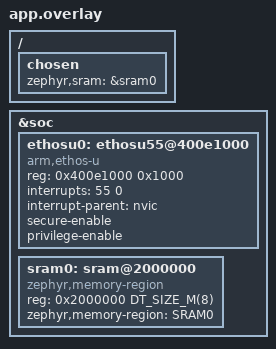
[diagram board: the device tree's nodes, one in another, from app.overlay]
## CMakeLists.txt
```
# SPDX-License-Identifier: Apache-2.0

cmake_minimum_required(VERSION 3.20.0)

# Select the AI layer's Kconfig fragments before Zephyr processes configuration.
list(APPEND EXTRA_CONF_FILE
  "${CMAKE_CURRENT_SOURCE_DIR}/ai_layer/components.conf"
  "${CMAKE_CURRENT_SOURCE_DIR}/ai_layer/operators.conf"
)

# Include the NPU node even when an older build cache has an empty overlay list.
if(NOT DTC_OVERLAY_FILE)
  set(DTC_OVERLAY_FILE "${CMAKE_CURRENT_SOURCE_DIR}/app.overlay")
endif()

find_package(Zephyr REQUIRED HINTS $ENV{ZEPHYR_BASE})
project(my_app)

add_subdirectory(ai_layer)

# Zephyr already provides sys/types.h for AC6; the bare-metal pack shim
# must not shadow it. Only libc++ needs compatibility adjustments here.
if(CMAKE_CXX_COMPILER_ID STREQUAL "ARMClang")
  # AC6 6.24's register coalescer crashes on this pack's quantization code
  # with hard-float at -Og/-O1; -O2 avoids it and keeps the kernel optimized.
  if(CONFIG_FP_HARDABI)
    get_target_property(_et_sources cmsis_executorch SOURCES)
    set(_et_quantize_workaround_applied FALSE)
    foreach(_source IN LISTS _et_sources)
      if(_source MATCHES "[/\\\\]op_quantize\\.cpp$")
        set_property(SOURCE "${_source}" TARGET_DIRECTORY cmsis_executorch
          APPEND PROPERTY COMPILE_OPTIONS -O2)
        set(_et_quantize_workaround_applied TRUE)
      endif()
    endforeach()
    if(NOT _et_quantize_workaround_applied)
      message(FATAL_ERROR
        "AC6 workaround could not find ExecuTorch op_quantize.cpp")
    endif()
  endif()

  # Zephyr's armstdc wrappers use #include_next to chain into AC6's C headers,
  # and AC6 6.24's libc++ wrappers must precede both (notably stddef.h).
  # Explicitly add both system include paths in order: libcxx -> armstdc -> include.
  get_filename_component(_ac6_bin "${CMAKE_CXX_COMPILER}" DIRECTORY)
  get_filename_component(_ac6_include "${_ac6_bin}/../include" ABSOLUTE)
  get_filename_component(_ac6_libcxx "${_ac6_include}/libcxx" ABSOLUTE)
  if(IS_DIRECTORY "${_ac6_libcxx}")
    target_include_directories(zephyr_interface SYSTEM BEFORE INTERFACE
      "$<$<COMPILE_LANGUAGE:CXX>:${_ac6_libcxx}>")
  endif()
  if(IS_DIRECTORY "${_ac6_include}")
    target_include_directories(zephyr_interface SYSTEM INTERFACE
      "${_ac6_include}")
  endif()
  zephyr_compile_options(
    "$<$<COMPILE_LANGUAGE:CXX>:-include${CMAKE_CURRENT_SOURCE_DIR}/src/zephyr_ac6_compat.hpp>")

  # Zephyr's CMake scatter generator disables CONFIG_STATIC_INIT_GNU,
  # omitting the constructor runner and the companion destructor handler.
  if(NOT CONFIG_STATIC_INIT_GNU)
    zephyr_linker_section_configure(SECTION ctors
      INPUT ".init_array*" SORT NAME KEEP
      SYMBOLS __ac6_init_array_start __ac6_init_array_end)
    zephyr_link_libraries("--keep=*.o(.init_array*)")
    target_sources(app PRIVATE src/zephyr_ac6_init.c
      "${ZEPHYR_BASE}/lib/cpp/abi/cpp_dtors.c")
  endif()

  # Zephyr hard-codes microlib for armlink. ExecuTorch's full libc++ needs
  # the standard Arm C runtime (wide strings and AEABI assertions).
  foreach(_elf zephyr_pre0 zephyr_pre1 zephyr_final)
    if(TARGET ${_elf})
      get_target_property(_libs ${_elf} LINK_LIBRARIES)
      list(REMOVE_ITEM _libs "--library_type=microlib")
      set_property(TARGET ${_elf} PROPERTY LINK_LIBRARIES "${_libs}")
    endif()
  endforeach()
endif()

target_sources(app PRIVATE
  src/main.c
  src/arm_embedded_module.cpp
)
target_include_directories(app PRIVATE src)
if(CONFIG_EXECUTORCH_MULTIPLE_TEST)
  target_sources(app PRIVATE src/executorch_multiple_test.cpp)
else()
  target_sources(app PRIVATE src/executorch_test.cpp)
endif()

# The Corstone FVP watches UART output for EOT (0x04). Physical targets must
# not receive this control character, so enable it only from the FVP context.
if(FVP_SHUTDOWN_ON_EOT)
  target_compile_definitions(app PRIVATE FVP_SHUTDOWN_ON_EOT=1)
endif()

# Keep runtime logging consistent with the existing AI layer configuration.
zephyr_compile_definitions(ET_LOG_ENABLED=0)
```

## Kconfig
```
# Copyright 2026 Arm Limited and/or its affiliates.
# SPDX-License-Identifier: Apache-2.0
mainmenu "ExecuTorch example"

choice EXECUTORCH_EXAMPLE
    prompt "ExecuTorch test"
    default EXECUTORCH_SINGLE_TEST

config EXECUTORCH_SINGLE_TEST
    bool "Single TinyCNN forward method"

config EXECUTORCH_MULTIPLE_TEST
    bool "Filter then classify with runtime shape constants"

endchoice

source "Kconfig.zephyr"
```

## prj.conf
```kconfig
# Zephyr driver configuration for the E8 Ethos-U55 with 256 MACs
# per cycle. These are Zephyr Kconfig symbols, not CMSIS-Ethos-U pack settings.
# Alif UART registers require 32-bit MMIO accesses. Byte writes to the
# NS16550 transmit holding register do not start transmission.
CONFIG_UART_NS16550_ACCESS_WORD_ONLY=y

CONFIG_ETHOS_U=y
CONFIG_ETHOS_U55_256=y
CONFIG_ETHOS_U_ARM=y
#CONFIG_ETHOS_U_LOG_LEVEL_NONE=y

# Ethos-U synchronization uses the kernel heap.
CONFIG_HEAP_MEM_POOL_SIZE=16384
# C++ allocations must use a heap initialized by Zephyr, including with AC6.
CONFIG_COMMON_LIBC_MALLOC=y
CONFIG_COMMON_LIBC_MALLOC_ARENA_SIZE=65536
CONFIG_LOG=y
# Keep the boot banner and kernel logs in order with the runtime's direct printf.
CONFIG_LOG_MODE_IMMEDIATE=y
CONFIG_ETHOS_U_LOG_LEVEL_INF=y
CONFIG_CACHE_MANAGEMENT=y
CONFIG_ETHOS_U_DCACHE=y

CONFIG_CPP=y
CONFIG_STD_CPP17=y

# Use the Cortex-M hardware FPU and pass floating-point arguments in FP registers.
CONFIG_FPU=y
CONFIG_FP_HARDABI=y

# Runtime loading uses C++ containers; the runner also prints float logits.
CONFIG_MAIN_STACK_SIZE=16384
CONFIG_REQUIRES_FLOAT_PRINTF=y

# Set y after selecting TinyCNNMultiple.pt2 in the csolution and regenerating ai_layer.
CONFIG_EXECUTORCH_MULTIPLE_TEST=n
```

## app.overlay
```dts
/* Copyright (c) Meta Platforms, Inc. and affiliates.
 * Copyright 2026 Arm Limited and/or its affiliates.
 * SPDX-License-Identifier: Apache-2.0
 */

/* The Ethos-U cannot DMA to the Cortex-M55 DTCM selected by the board DTS.
 * Combine SRAM0 and SRAM1 into one NPU-accessible application RAM region.
 */
/delete-node/ &sram0;
/delete-node/ &sram1;

&soc {
	ethosu0: ethosu55@400e1000 {
		compatible = "arm,ethos-u";
		reg = <0x400e1000 0x1000>;
		interrupts = <55 0>;
		interrupt-parent = <&nvic>;
		secure-enable;
		privilege-enable;
		status = "okay";
	};

	sram0: sram@2000000 {
		compatible = "zephyr,memory-region", "mmio-sram";
		reg = <0x2000000 DT_SIZE_M(8)>;
		zephyr,memory-region = "SRAM0";
	};
};

/ {
	chosen {
		zephyr,sram = &sram0;
	};
};
```

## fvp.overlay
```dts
/* SPDX-License-Identifier: Apache-2.0 */

/* Use ISRAM for writable data because the Ethos-U DMA cannot access DTCM. */
/ {
	chosen {
		zephyr,sram = &isram;
	};
};
```

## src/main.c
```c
/*
 * Copyright (c) 2012-2014 Wind River Systems, Inc.
 *
 * SPDX-License-Identifier: Apache-2.0
 */

#include <errno.h>
#include <inttypes.h>
#include <stdio.h>

#include <zephyr/device.h>
#include <zephyr/devicetree.h>

#include <ethosu_driver.h>

#include "executorch_test.h"

#define NPU_NODE DT_NODELABEL(ethosu0)

static int finish(int result)
{
#ifdef FVP_SHUTDOWN_ON_EOT
	/* fvp_config.txt has shutdown_on_eot=1, so this ends an FVP run promptly. */
	putchar('\x04');
	fflush(stdout);
#endif
	return result;
}

int main(void)
{
	const struct device *npu = DEVICE_DT_GET(NPU_NODE);
	struct ethosu_driver_version version;
	struct ethosu_hw_info hw;
	struct ethosu_driver *drv;
	int ret = 0;

	printf("Hello World! %s\n", CONFIG_BOARD_TARGET);
	printf("Ethos-U55 driver communication check\n");
	printf("Device: %s, base: 0x%08" PRIxPTR ", IRQ: %u\n", npu->name,
	       (uintptr_t)DT_REG_ADDR(NPU_NODE), DT_IRQN(NPU_NODE));

	ethosu_get_driver_version(&version);
	printf("Driver version: %u.%u.%u\n", version.major, version.minor, version.patch);

	/* Do not reserve a driver if initialization failed: reservation would block. */
	if (!device_is_ready(npu)) {
		printf("ERROR: Ethos-U55 device initialization failed. Check the driver logs "
		       "and the board's NPU power, clock and security configuration.\n");
		return finish(-ENODEV);
	}

	drv = ethosu_reserve_driver();
	if (drv == NULL) {
		printf("ERROR: Could not reserve the Ethos-U55 driver.\n");
		return finish(-ENODEV);
	}

	/* This API reads the NPU's ID and CONFIG registers through the core driver. */
	ethosu_get_hw_info(drv, &hw);
	printf("Hardware architecture: %" PRIu32 ".%" PRIu32 ".%" PRIu32 "\n",
	       hw.version.arch_major_rev, hw.version.arch_minor_rev,
	       hw.version.arch_patch_rev);
	printf("Hardware revision: %" PRIu32 ".%" PRIu32 " (status %" PRIu32 ")\n",
	       hw.version.version_major, hw.version.version_minor, hw.version.version_status);
	printf("Product revision: %" PRIu32 "\n", hw.version.product_major);
	printf("Command stream version: %" PRIu32 "\n", hw.cfg.cmd_stream_version);
	printf("Custom DMA: %" PRIu32 "\n", hw.cfg.custom_dma);

	/* macs_per_cc is encoded as log2(MACs per cycle) by the hardware. */
	if (hw.cfg.macs_per_cc < 32U) {
		uint32_t macs = UINT32_C(1) << hw.cfg.macs_per_cc;

		printf("MACs per cycle: %" PRIu32 "\n", macs);
		if (macs != 256U) {
			printf("ERROR: Expected the E8's 256-MAC Ethos-U55 configuration.\n");
			ret = -EINVAL;
		}
	} else {
		printf("ERROR: Invalid MAC configuration: %" PRIu32 "\n", hw.cfg.macs_per_cc);
		ret = -EINVAL;
	}

	ethosu_release_driver(drv);
	if (ret == 0) {
		printf("Ethos-U55 driver communication OK (ID/configuration read; no inference).\n");
		return finish(executorch_run_test());
	}

	return finish(ret);
}
```

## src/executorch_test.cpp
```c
// Copyright 2026 Arm Limited and/or its affiliates.
// SPDX-License-Identifier: Apache-2.0
// Adapted from CMSIS-Executorch/src/app_main.cpp for the Zephyr application.

#include <array>
#include <cstdint>
#include <cstdio>
#include <cstring>
#include <memory>

#include <executorch/extension/data_loader/buffer_data_loader.h>
#include <executorch/runtime/core/evalue.h>
#include <executorch/runtime/core/exec_aten/exec_aten.h>
#include <executorch/runtime/core/memory_allocator.h>
#include <executorch/runtime/platform/runtime.h>

#include "arm_embedded_module.hpp"
#include "executorch_test.h"
#include "TinyCNN_pte.h"

using arm::embedded::EmbeddedModule;
using executorch::aten::DimOrderType;
using executorch::aten::ScalarType;
using executorch::aten::SizesType;
using executorch::aten::Tensor;
using executorch::aten::TensorImpl;
using executorch::extension::BufferDataLoader;
using executorch::runtime::EValue;
using executorch::runtime::MemoryAllocator;

namespace {

#ifndef EXECUTORCH_TARGET_NAME
#define EXECUTORCH_TARGET_NAME "Ethos-U55-256"
#endif

// TinyCNN needs much less space than the original example's two 4 MiB pools.
constexpr size_t kMethodPoolSize = 128 * 1024;
constexpr size_t kTempPoolSize = 64 * 1024;

alignas(64) uint8_t g_method_pool[kMethodPoolSize];
// The default .bss is writable system SRAM on the supplied targets.
alignas(64) uint8_t g_temp_pool[kTempPoolSize];

} // namespace

extern "C" int executorch_run_test(void)
{
  executorch::runtime::runtime_init();
  printf("ExecuTorch %s application: %lu byte model\n", EXECUTORCH_TARGET_NAME,
         TinyCNN_pte_size);

  // Devicetree memory-region sections are NOLOAD and are not zeroed at boot.
  std::memset(g_temp_pool, 0, sizeof(g_temp_pool));

  EmbeddedModule module(
      TinyCNN_pte, TinyCNN_pte_size,
      std::make_unique<BufferDataLoader>(TinyCNN_pte, TinyCNN_pte_size),
      std::make_unique<MemoryAllocator>(kMethodPoolSize, g_method_pool),
      std::make_unique<MemoryAllocator>(kTempPoolSize, g_temp_pool));

  // Same deterministic image values as the CMSIS pack example. The supplied
  // The PTE exposes NCHW, whereas the original runner hard-codes NHWC.
  alignas(16) static float input_data[16 * 16 * 3];
  auto method_meta = module.method_meta("forward");
  if (!method_meta.ok()) {
    printf("Could not read forward metadata (err=%u)\nTest_result: FAIL\n",
           static_cast<unsigned>(method_meta.error()));
    return 1;
  }
  if (method_meta->num_inputs() != 1) {
    printf("forward expected one input\nTest_result: FAIL\n");
    return 1;
  }
  auto input_meta = method_meta->input_tensor_meta(0);
  if (!input_meta.ok() || input_meta->scalar_type() != ScalarType::Float ||
      input_meta->sizes().size() != 4 || input_meta->dim_order().size() != 4 ||
      input_meta->nbytes() != sizeof(input_data)) {
    printf("forward expected a rank-four RGB image with 768 floats\n"
           "Test_result: FAIL\n");
    return 1;
  }

  for (size_t i = 0; i < sizeof(input_data) / sizeof(input_data[0]); ++i) {
    input_data[i] = static_cast<float>(i % 32) / 32.0f - 0.5f;
  }
  std::array<SizesType, 4> sizes;
  std::array<DimOrderType, 4> dim_order;
  for (size_t i = 0; i < sizes.size(); ++i) {
    sizes[i] = input_meta->sizes()[i];
    dim_order[i] = input_meta->dim_order()[i];
  }
  printf("Input shape: [%ld, %ld, %ld, %ld]\n", static_cast<long>(sizes[0]),
         static_cast<long>(sizes[1]), static_cast<long>(sizes[2]),
         static_cast<long>(sizes[3]));
  TensorImpl input_impl(ScalarType::Float, sizes.size(), sizes.data(), input_data,
                        dim_order.data());
  Tensor input(&input_impl);

  auto outputs = module.forward(input);
  if (!outputs.ok()) {
    printf("forward failed (err=%u)\nTest_result: FAIL\n",
           static_cast<unsigned>(outputs.error()));
    return 1;
  }
  if (outputs->size() != 1 || !outputs->front().isTensor()) {
    printf("forward expected one output tensor\nTest_result: FAIL\n");
    return 1;
  }

  const EValue& out = outputs->front();
  Tensor tensor = out.toTensor();
  const auto num_output_elements = tensor.numel();
  if (tensor.scalar_type() != ScalarType::Float || num_output_elements != 10) {
    printf("forward expected ten float logits\nTest_result: FAIL\n");
    return 1;
  }

  // The signed element count is positive after the ten-logit check above.
  const auto output_count = static_cast<size_t>(num_output_elements);
  printf("Output: %zu element(s):", output_count);
  const float* data = tensor.const_data_ptr<float>();
  for (size_t i = 0; i < output_count; ++i) {
    printf(" %.4f", static_cast<double>(data[i]));
  }
  printf("\nTest_result: PASS\n");
  fflush(stdout);
  return 0;
}
```

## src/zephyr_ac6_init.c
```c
// Copyright 2026 Arm Limited and/or its affiliates.
// SPDX-License-Identifier: Apache-2.0
#include <zephyr/init.h>
#include <stdint.h>

typedef void (*constructor_fn)(void);
extern const uint32_t __ac6_init_array_start[];
extern const uint32_t __ac6_init_array_end[];

static int ac6_static_init(void)
{
  for (const uint32_t *entry = __ac6_init_array_start;
       entry != __ac6_init_array_end; ++entry) {
    if (*entry != 0U) {
      // armlink resolves .init_array entries relative to their own slot.
      // Unsigned addition handles negative offsets and preserves the Thumb bit.
      constructor_fn fn = (constructor_fn)((uintptr_t)entry + *entry);
      fn();
    }
  }
  return 0;
}

// Run after POST_KERNEL and before main, as Zephyr's GNU initializer does.
SYS_INIT(ac6_static_init, APPLICATION, 0);
```
